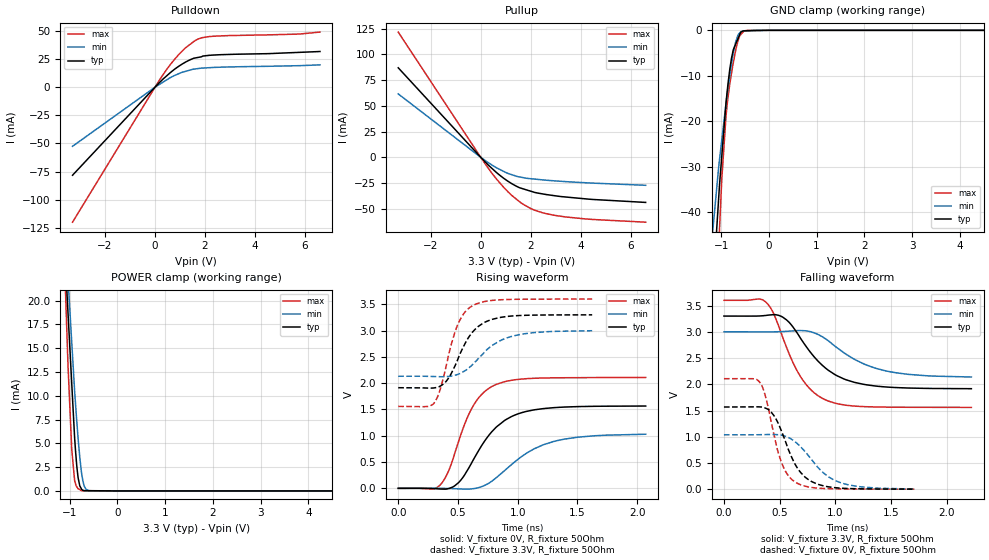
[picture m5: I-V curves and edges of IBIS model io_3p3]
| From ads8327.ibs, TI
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|   io_3p3 Model
[Model]   io_3p3
Model_type   I/O
Polarity   Non-Inverting
Enable   Active-Low
Vinl = 1.15
Vinh = 2.14
Vmeas = 1.65
Vref = 1.65
Cref = 30pF
Rref = 50
|   typ   min   max
|   (nom PVT)   (Fast PVT)   (slow PVT)
|C_comp from frequency sweep method(F=50MHz)
C_comp   3.799e-12   3.676e-12   3.917e-12
|ON state : BUFFER OUTPUT TURNED HIGH
|C_comp   4.210e-12   4.098e-12   4.339e-12
|OFF state: BUFFER OUTPUT TURNED LOW
|C_comp   3.799e-12   3.676e-12   3.917e-12
|C_comp from LC tank measurement(L=1nH)
|C_comp   3.031e-12   2.7275e-12  3.2545e-12
|OFF state: BUFFER OUTPUT TURNED LOW
|Resonant Frequency(Hz)   2.970e+09   3.100e+09   2.880e+09
|C_comp   2.874e-12   2.638e-12   3.057e-12
|ON state : BUFFER OUTPUT TURNED HIGH
|Resonant Frequency(Hz)   2.820e+09   3.000e+09   2.710e+09
|C_comp   3.188e-12   2.817e-12   3.452e-12
| Where nom  PVT is Nominal Process,  3.3V,  28C
|   Fast PVT is Strong Process,   3.6V,  -40C
|   Slow PVT is Weak Process,   3V,  88C
[Model Spec]
Vinl   1.15   1.05   1.26
Vinh   2.14   1.95   2.34
[Voltage Range]   3.3   3   3.6
|Ambient Temperature   25   85   -40
|Junction Temperature
[Temperature Range]   28   88   -40
[Pullup Reference]   3.3   3   3.6
[Pulldown Reference]   0   0   0
[Power Clamp Reference]   3.3   3   3.6
[GND Clamp Reference]   0   0   0
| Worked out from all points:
|   slope of the pulldown table from 0 to 0.495 V, typ, clamps not added: 46.5 ohm
|   slope of the pullup table from 0 to 0.495 V, typ, clamps not added: 41.8 ohm
|   GND clamp passes 1 mA (typ) near -0.61 V on its own axis
|   POWER clamp passes 1 mA (typ) near -0.81 V on its own axis
|   falling waveform, V_fixture 3.3V, R_fixture 50Ohm: 20-80 % time 347ps typ, 417ps min, 273ps max; typ from 3.3 V to 1.92 V
|   rising waveform, V_fixture 0V, R_fixture 50Ohm: 20-80 % time 298ps typ, 387ps min, 225ps max; typ from 0 V to 1.56 V
|   rising waveform, V_fixture 3.3V, R_fixture 50Ohm: 20-80 % time 197ps typ, 269ps min, 152ps max; typ from 1.91 V to 3.3 V
|   falling waveform, V_fixture 0V, R_fixture 50Ohm: 20-80 % time 203ps typ, 281ps min, 151ps max; typ from 1.57 V to 0.004 V
[Pulldown]
|   Voltage   I(typ)   I(min)   I(max)
-3.3V     -78.31mA   -52.56mA   -120.1mA
172.8mV   4.001mA    2.441mA    6.177mA
478.8mV   10.34mA    6.702mA    16.15mA
770.4mV   15.77mA    10.32mA    24.48mA
1.246V    22.65mA    14.27mA    35.48mA
1.554V    25.79mA    16.09mA    40.64mA
1.706V    26.43mA    16.53mA    42.69mA
2.167V    28.35mA    17.37mA    45.04mA
5.778V    31.01mA    19.17mA    47.29mA
6.6V      31.76mA    19.87mA    49.04mA
[GND Clamp]
|   Voltage   I(typ)   I(min)   I(max)
-3.3V     -511.9mA   -370.7mA   -746.5mA
-1.204V   -62.26mA   -47.41mA   -87.55mA
-1.102V   -45.26mA   -35.81mA   -59.55mA
-1.033V   -33.91mA   -28.37mA   -43.59mA
-986.4mV  -27.74mA   -24.15mA   -32.78mA
-896.4mV  -15.82mA   -16mA      -18.72mA
-860.4mV  -12.18mA   -13.11mA   -15.1mA
-782.1mV  -6.131mA   -7.349mA   -9.442mA
-705mV    -3.276mA   -2.926mA   -4.937mA
-608.4mV  -871.8uA   -542.8uA   -1.177mA
-549mV    -198.7uA   -140.8uA   -475.7uA
6.6V      0A         0A         0A
[Pullup]
|   Voltage   I(typ)   I(min)   I(max)
-3.3V     86.97mA    61.59mA    121.7mA
234mV     -5.884mA   -4.117mA   -8.357mA
604.8mV   -14.26mA   -9.827mA   -20.34mA
939.6mV   -20.77mA   -13.98mA   -29.76mA
1.246V    -25.69mA   -16.95mA   -37.13mA
1.609V    -30.02mA   -19.39mA   -44.24mA
2.167V    -34.22mA   -21.23mA   -51.5mA
2.624V    -36.23mA   -22.29mA   -54.8mA
3.089V    -37.81mA   -23.15mA   -56.94mA
4.497V    -41.02mA   -25.13mA   -60.46mA
6.6V      -43.88mA   -27.24mA   -63.09mA
[POWER Clamp]
|   Voltage   I(typ)   I(min)   I(max)
-3.3V     177.2mA    159.5mA    202.3mA
-1.451V   64.21mA    57.65mA    74.35mA
-1.053V   20.33mA    23.75mA    15.75mA
-1.033V   18.48mA    22.09mA    12.93mA
-957.6mV  11.32mA    15.65mA    4.394mA
-896.4mV  5.55mA     10.45mA    1.07mA
-858mV    2.977mA    7.726mA    487.3uA
-825mV    1.439mA    5.582mA    239.7uA
-756mV    230.5uA    2.053mA    40.29uA
-696mV    31.36uA    516.1uA    6.841uA
-591mV    26.61uA    22.96uA    1.622uA
6.6V      0A         0A         0A
[Ramp]
R_load = 50
|   typ   min   max
dV/dt_r   0.940446/2.96981e-10   0.622285/3.93197e-10   1.2656/2.24531e-10
dV/dt_f   0.831517/3.48263e-10   0.520883/4.24422e-10   1.22452/2.72995e-10
[Falling Waveform]
V_fixture = 3.3V
V_fixture_min = 3V
V_fixture_max = 3.6V
R_fixture = 50Ohm
|   Time   V(typ)   V(min)   V(max)
0s        3.3V       3V         3.6V
380ps     3.313V     2.999V     3.559V
450ps     3.327V     3V         3.328V
528ps     3.279V     3.005V     2.89V
690ps     2.867V     3.024V     2.137V
786ps     2.584V     2.997V     1.884V
918ps     2.298V     2.857V     1.698V
1.1ns     2.084V     2.568V     1.6V
1.38ns    1.963V     2.295V     1.568V
2.22ns    1.917V     2.139V     1.561V
[Rising Waveform]
V_fixture = 0V
V_fixture_min = 0V
V_fixture_max = 0V
R_fixture = 50Ohm
|   Time   V(typ)   V(min)   V(max)
0s        1.203nV    1.361nV    1.013nV
352ps     -12.78mV   285.7uV    66.67mV
426ps     -1.269mV   -2.898mV   352.7mV
476ps     53.33mV    -7.072mV   687.4mV
616ps     488.1mV    -9.436mV   1.521V
710ps     852.9mV    42.58mV    1.811V
818ps     1.157V     196.5mV    1.973V
1.004ns   1.417V     555.4mV    2.071V
1.3ns     1.533V     889.8mV    2.101V
2.072ns   1.565V     1.029V     2.107V
[Rising Waveform]
V_fixture = 3.3V
V_fixture_min = 3V
V_fixture_max = 3.6V
R_fixture = 50Ohm
|   Time   V(typ)   V(min)   V(max)
0s        1.913V     2.131V     1.558V
300ps     1.909V     2.125V     1.619V
340ps     1.93V      2.123V     1.802V
400ps     2.03V      2.124V     2.31V
492ps     2.414V     2.161V     3.077V
554ps     2.728V     2.229V     3.337V
626ps     2.98V      2.36V      3.477V
788ps     3.213V     2.718V     3.573V
962ps     3.278V     2.896V     3.592V
1.624ns   3.298V     2.996V     3.598V
[Falling Waveform]
V_fixture = 0V
V_fixture_min = 0V
V_fixture_max = 0V
R_fixture = 50Ohm
|   Time   V(typ)   V(min)   V(max)
0s        1.568V     1.039V     2.108V
332ps     1.568V     1.041V     2.01V
368ps     1.55V      1.043V     1.806V
424ps     1.47V      1.045V     1.282V
506ps     1.163V     1.036V     573.9mV
568ps     815.6mV    997.2mV    289.4mV
656ps     414.9mV    874.3mV    118.7mV
796ps     138.3mV    541mV      32.89mV
1.05ns    22.5mV     123.5mV    8.377mV
1.714ns   3.648mV    5.763mV    3.245mV
